VERSION 5.7 ;
  NOWIREEXTENSIONATPIN ON ;
  DIVIDERCHAR "/" ;
  BUSBITCHARS "[]" ;
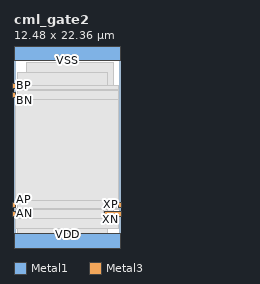
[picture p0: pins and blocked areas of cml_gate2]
MACRO cml_gate2
  CLASS BLOCK ;
  FOREIGN cml_gate2 ;
  ORIGIN 0.000 0.000 ;
  SIZE 12.480 BY 22.360 ;
  PIN VDD
    DIRECTION INOUT ;
    USE POWER ;
    PORT
      LAYER Metal1 ;
        RECT 0.000 -1.000 12.480 1.000 ;
    END
  END VDD
  PIN VSS
    DIRECTION INOUT ;
    USE GROUND ;
    PORT
      LAYER Metal1 ;
        RECT 0.000 21.360 12.480 23.360 ;
    END
  END VSS
  PIN AN
    DIRECTION INPUT ;
    USE SIGNAL ;
    ANTENNAGATEAREA 0.826800 ;
    PORT
      LAYER Metal3 ;
        RECT -0.150 3.000 0.150 3.600 ;
    END
  END AN
  PIN AP
    DIRECTION INPUT ;
    USE SIGNAL ;
    ANTENNAGATEAREA 0.826800 ;
    PORT
      LAYER Metal3 ;
        RECT -0.150 4.100 0.150 4.700 ;
    END
  END AP
  PIN XN
    DIRECTION OUTPUT ;
    USE SIGNAL ;
    ANTENNADIFFAREA 1.208400 ;
    PORT
      LAYER Metal3 ;
        RECT 10.685 3.000 12.630 3.600 ;
    END
  END XN
  PIN XP
    DIRECTION OUTPUT ;
    USE SIGNAL ;
    ANTENNADIFFAREA 2.416800 ;
    PORT
      LAYER Metal3 ;
        RECT 12.330 4.100 12.630 4.700 ;
    END
  END XP
  PIN BN
    DIRECTION INPUT ;
    USE SIGNAL ;
    ANTENNAGATEAREA 0.826800 ;
    PORT
      LAYER Metal3 ;
        RECT -0.150 17.000 0.150 17.600 ;
    END
  END BN
  PIN BP
    DIRECTION INPUT ;
    USE SIGNAL ;
    ANTENNAGATEAREA 0.826800 ;
    PORT
      LAYER Metal3 ;
        RECT -0.150 18.100 0.150 18.700 ;
    END
  END BP
  OBS
      LAYER GatPoly ;
        RECT 1.585 1.610 11.760 20.720 ;
      LAYER Metal1 ;
        RECT 1.450 1.590 11.690 21.180 ;
      LAYER Metal2 ;
        RECT 0.400 0.230 10.980 19.940 ;
      LAYER Metal3 ;
        RECT 0.360 17.890 12.330 18.400 ;
        RECT 0.150 17.810 12.330 17.890 ;
        RECT 0.360 16.790 12.330 17.810 ;
        RECT 0.150 4.910 12.330 16.790 ;
        RECT 0.360 3.890 12.120 4.910 ;
        RECT 0.150 3.810 12.330 3.890 ;
        RECT 0.360 2.790 10.475 3.810 ;
        RECT 0.150 1.610 12.330 2.790 ;
  END
END cml_gate2
END LIBRARY

